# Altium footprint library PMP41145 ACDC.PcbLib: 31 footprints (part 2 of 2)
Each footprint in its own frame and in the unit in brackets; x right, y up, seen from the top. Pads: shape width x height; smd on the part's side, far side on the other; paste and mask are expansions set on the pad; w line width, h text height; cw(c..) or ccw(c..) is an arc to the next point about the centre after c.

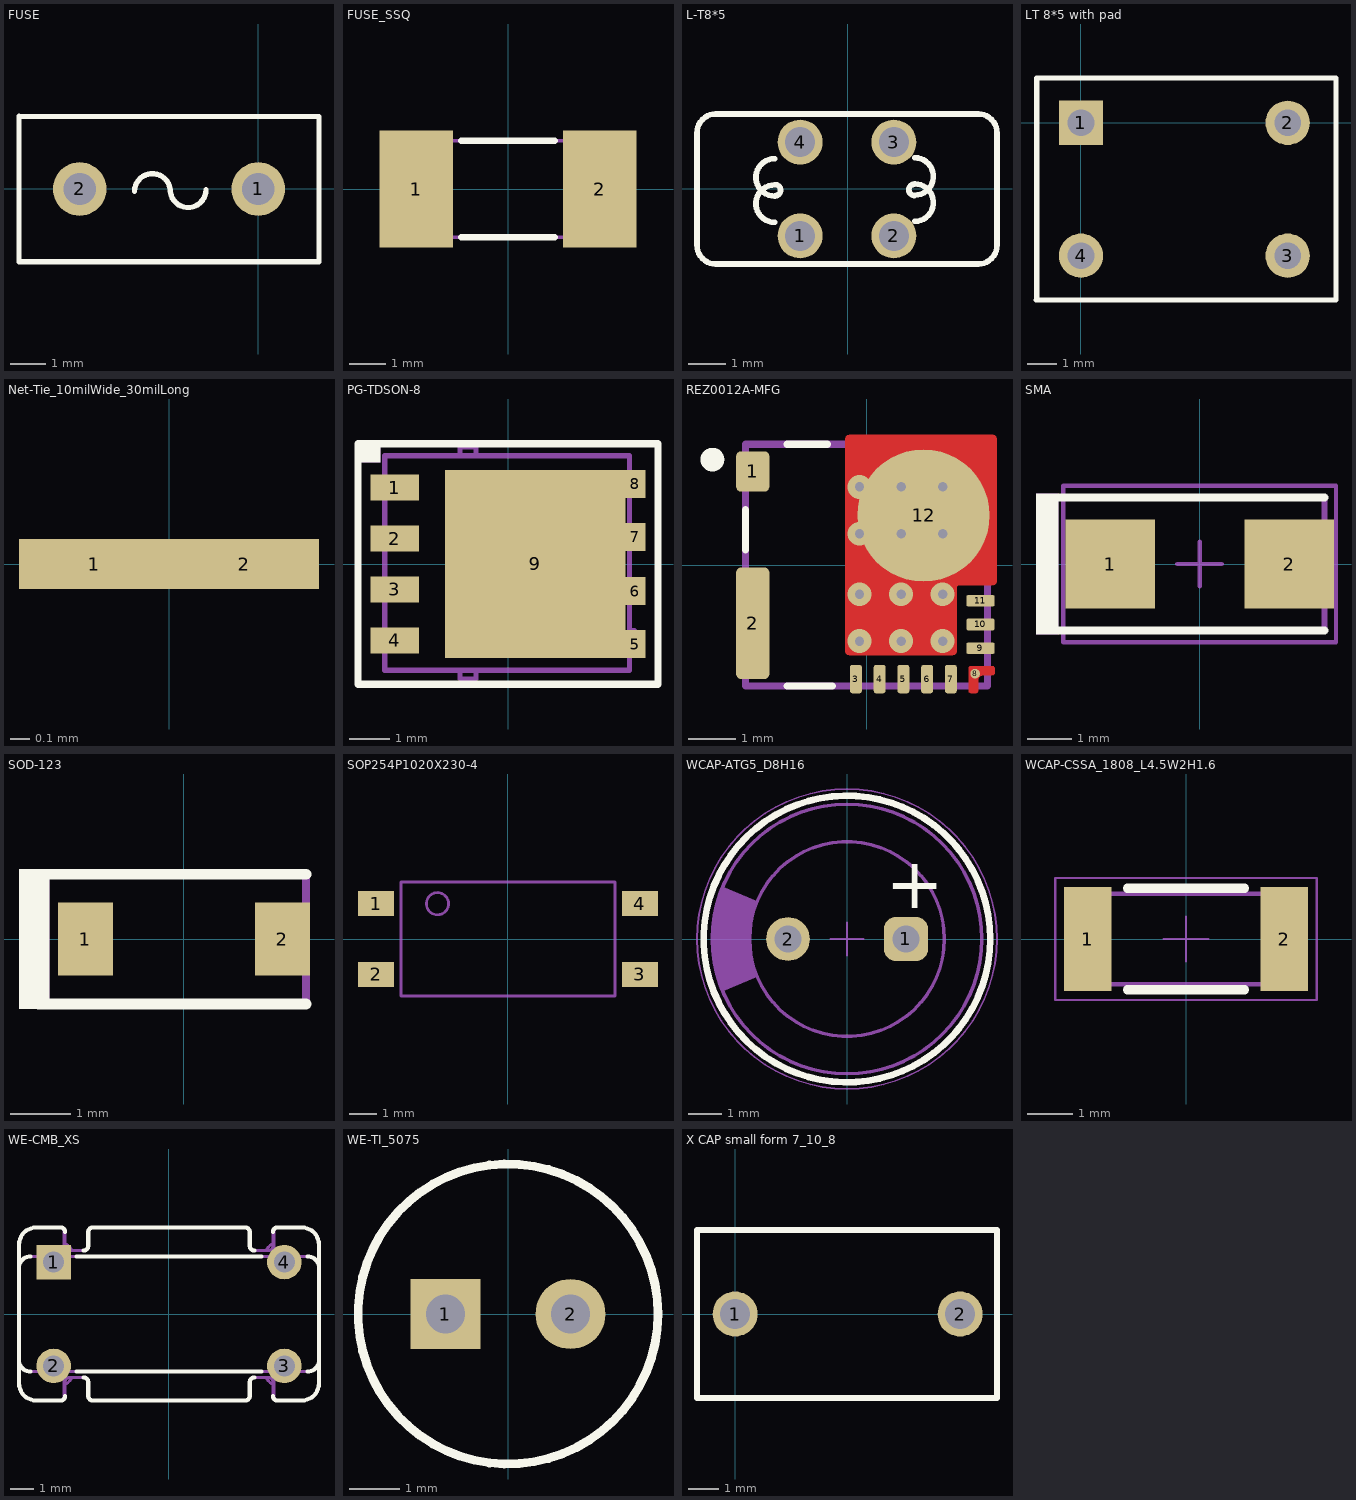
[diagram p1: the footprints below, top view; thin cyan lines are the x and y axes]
## FUSE [mm]
height 0.9
pads (2):
  round 1.5 hole 0.9: 1(0,0) 2(-5,0)
Top Overlay:
  lines w0.15: -3.465,-0.068 cw(c-2.965,-0.068) -2.465,-0.068 ; -2.465,-0.018 ccw(c-1.965,-0.018) -1.465,-0.018 ; -6.7,-2.032 -6.7,2.032 1.7,2.032 1.7,-2.032 -6.7,-2.032
3D body: height 5, standoff 0, extent -6.7,-2.032 1.7,2.032

## FUSE_SSQ [mm] "Bel Fuse"
height 2.64
pads (2):
  rect 2x3.18 smd: 1(-2.5,0) 2(2.5,0)
Top Overlay:
  lines w0.178: -1.27,-1.32 1.27,-1.32 ; -1.27,1.32 1.27,1.32
Mechanical 5:
  lines w0.1: -3.175,-1.32 3.175,-1.32 3.175,1.32 -3.175,1.32 -3.175,-1.32
  text ".Designator" at -2.032,-0.508 h1.02
3D body: height 2.64, standoff 0, extent -3.175,-1.32 3.17,1.32

## L-T8*5 [mm]
height 1
pads (4):
  round 1.2 hole 0.8: 1(-1.272,-1.253) 2(1.228,-1.253) 3(1.228,1.247) 4(-1.272,1.247)
Top Overlay:
  lines w0.15: -1.951,-0.892 cw(c-1.951,-0.392) -1.951,0.108 ; -1.951,-0.193 cw(c-1.951,0.307) -1.951,0.807 ; -1.943,-0.185 ccw(c-1.943,-0.035) -1.943,0.115 ; 1.776,-0.175 cw(c1.776,-0.025) 1.776,0.125 ; 1.784,-0.867 ccw(c1.784,-0.367) 1.784,0.133 ; 1.784,-0.168 ccw(c1.784,0.332) 1.784,0.832 ; -4.022,-1.503 ccw(c-3.522,-1.503) -3.522,-2.003 3.478,-2.003 ccw(c3.478,-1.503) 3.978,-1.503 3.978,1.497 ccw(c3.478,1.497) 3.478,1.997 -3.522,1.997 ccw(c-3.522,1.497) -4.022,1.497 -4.022,-1.503
3D body "lf2.stp": height 10, standoff 0, extent -4.9,-2.9 5.1,3.1

## LT 8*5 with pad [mm] "WE-CMB Series Size XS"
height 18
pads (4):
  rect 1.5x1.5 hole 0.9: 1(0,0)
  round 1.5 hole 0.9: 2(7,0) 3(7,-4.5) 4(0,-4.5)
Top Overlay:
  lines w0.178: -1.524,-6 8.636,-6 8.636,1.517 -1.5,1.517 -1.5,-4.25 -1.5,-6

## Net-Tie_10milWide_30milLong [mil] "10mil net tie, no solder mask opening, no solder paste"
pads (2):
  rect 30x10 smd paste-5 mask-5: 1(-15,0) 2(15,0)

## PG-TDSON-8 [mm] "Infineon recommended land pattern"
height 1.1
pads (9):
  rect 1.2x0.65 smd: 1(-2.825,1.905) 2(-2.825,0.635) 3(-2.825,-0.635) 4(-2.825,-1.905)
  rect 0.5x0.7 smd: 5(3.175,-2) 6(3.175,-0.675) 7(3.175,0.675) 8(3.175,2)
  rect 4.5x4.7 smd paste-2.25: 9(0.675,0)
Top Overlay:
  rectangle: -3.742,2.528 -3.177,2.975
  lines w0.178: -3.74,-3 -0.105,-3 3.74,-3 3.74,0 3.74,3 0.105,3 -3.74,3 -3.74,0 -3.74,-3
Top Paste:
  rectangle: -1.475,-2.25 -0.242,-0.95
  rectangle: -1.475,-0.65 -0.242,0.65
  rectangle: 1.591,-2.25 2.824,-0.95
  rectangle: 0.058,-0.65 1.291,0.65
  rectangle: 0.058,-2.25 1.291,-0.95
  rectangle: -1.475,0.95 -0.242,2.25
  rectangle: 1.591,-0.65 2.824,0.65
  rectangle: 0.058,0.95 1.291,2.25
  rectangle: 1.591,0.95 2.824,2.25
Mechanical 5:
  rectangle: -3.742,2.528 -3.177,2.975
  lines w0.127: -3.075,-2.1 -3.2,-2.1 -3.2,-1.66 -3.075,-1.66 ; -3.075,-0.83 -3.2,-0.83 -3.2,-0.39 -3.075,-0.39 ; -3.075,0.44 -3.2,0.44 -3.2,0.88 -3.075,0.88 ; -3.075,1.71 -3.2,1.71 -3.2,2.15 -3.075,2.15 ; -1.2,-2.65 -1.2,-2.87 -0.8,-2.87 -0.8,-2.65 ; -1.2,2.7 -1.2,2.92 -0.8,2.92 -0.8,2.7 ; 3.025,-2.1 3.15,-2.1 3.15,-1.66 3.025,-1.66 ; 3.025,-0.83 3.15,-0.83 3.15,-0.39 3.025,-0.39 ; 3.025,0.44 3.15,0.44 3.15,0.88 3.025,0.88 ; 3.025,1.71 3.15,1.71 3.15,2.15 3.025,2.15 ; -3.075,-2.65 3.025,-2.65 3.025,2.7 -3.075,2.7 -3.075,-2.65
  text ".Designator" at -1.925,-0.5 h1.02
3D body "PG-TDSON-8.stp": height 1.1, standoff 0, extent -3.175,-2.895 3.175,2.895

## REZ0012A-MFG [mm]
pads (12):
  rrect29% 0.7x0.85 smd paste-1000 mask-1000: 1(-2.4,1.975)
  rrect29% 0.7x2.35 smd paste-1000 mask-1000: 2(-2.4,-1.225)
  rrect40% 0.25x0.6 smd paste+0 mask+0: 3(-0.225,-2.4) 4(0.275,-2.4) 5(0.775,-2.4) 6(1.275,-2.4) 7(1.775,-2.4)
  round 0.203 smd paste+0 mask+0: 8(2.288,-2.288)
  rrect40% 0.6x0.25 smd paste+0 mask+0: 9(2.4,-1.75) 10(2.4,-1.25) 11(2.4,-0.75)
  round 2.788 smd paste-1000 mask-1000: 12(1.199,1.048)
via -0.15,-1.6 diameter 0.5 hole 0.2
via 0.725,-1.6 diameter 0.5 hole 0.2
via 1.6,-1.6 diameter 0.5 hole 0.2
via -0.15,-0.61 diameter 0.5 hole 0.2
via 0.725,-0.61 diameter 0.5 hole 0.2
via 1.6,-0.61 diameter 0.5 hole 0.2
via -0.15,0.66 diameter 0.5 hole 0.2
via 0.725,0.66 diameter 0.5 hole 0.2
via 1.6,0.66 diameter 0.5 hole 0.2
via 1.6,1.65 diameter 0.5 hole 0.2
via 0.725,1.65 diameter 0.5 hole 0.2
via -0.15,1.65 diameter 0.5 hole 0.2
Top Layer:
  region: -0.45,2.65 -0.45,2.67 -0.435,2.707 -0.407,2.735 -0.37,2.75 -0.35,2.75 2.648,2.75 2.668,2.75 2.705,2.735 2.733,2.707 2.748,2.67 2.748,2.65 2.748,-0.325 2.748,-0.345 2.733,-0.382 2.705,-0.41 2.668,-0.425 2.648,-0.425 1.95,-0.425 1.94,-0.426 1.922,-0.433 1.908,-0.447 1.901,-0.465 1.9,-0.475 1.9,-1.8 1.9,-1.82 1.885,-1.857 1.857,-1.885 1.82,-1.9 1.8,-1.9 -0.35,-1.9 -0.37,-1.9 -0.407,-1.885 -0.435,-1.857 -0.45,-1.82 -0.45,-1.8
  region: 2.2,-2.7 2.19,-2.7 2.172,-2.692 2.158,-2.678 2.15,-2.66 2.15,-2.65 2.15,-2.175 2.15,-2.165 2.158,-2.147 2.172,-2.133 2.19,-2.125 2.2,-2.125 2.65,-2.125 2.66,-2.125 2.678,-2.133 2.692,-2.147 2.7,-2.165 2.7,-2.175 2.7,-2.275 2.7,-2.285 2.692,-2.303 2.678,-2.317 2.66,-2.325 2.65,-2.325 2.45,-2.325 2.43,-2.327 2.394,-2.342 2.367,-2.369 2.352,-2.405 2.35,-2.425 2.35,-2.65 2.35,-2.66 2.342,-2.678 2.328,-2.692 2.31,-2.7 2.3,-2.7
Top Overlay:
  circle w0.25: c-3.25,2.225 r0.125
  lines w0.15: -2.55,0.325 -2.55,1.175 ; -1.675,-2.55 -0.725,-2.55 ; -1.675,2.55 -0.825,2.55
Top Paste:
  drawing of 20 lines, arcs and shapes, not listed
Top Solder:
  drawing of 4 lines, arcs and shapes, not listed
Mechanical 5:
  lines w0.15: -2.55,-2.55 -2.55,2.55 2.55,2.55 2.55,-2.55 -2.55,-2.55
  text ".Designator" at 0.049,0.242 h0.5
3D body "IC_UCG28682_VQFN12.STEP": height 1, standoff 0, extent -2.5,-2.5 2.5,2.5

## SMA [mm] "Molded Diode, 2-Leads, Body 4.3x2.6mm, IPC Medium Density, based on OnSemi component dimensions and land pattern"
height 2.27
pads (2):
  rect 2x2 smd: 1(-2,0) 2(2,0)
Top Overlay:
  rectangle: -3.657,-1.576 -3.149,1.574
  lines w0.178: -3.327,-1.486 2.794,-1.486 ; -3.327,1.486 2.794,1.486
Mechanical 5:
  rectangle: -3.657,-1.576 -3.149,1.574
  lines w0.127: -3.327,-1.486 2.794,-1.486 2.794,1.486 -3.327,1.486
  text ".Designator" at -2.769,-0.33 h1.02
Mechanical 15:
  lines w0.1: -0.5,0 0.5,0 ; 0,-0.5 0,0.5 ; -3.05,-1.75 -3.05,1.75 3.05,1.75 3.05,-1.75 -3.05,-1.75
3D body "SMA_nominal.stp": height 2.42, standoff 0.02, extent -2.6,-1.3 2.6,1.3

## SOD-123 [mm] "On Semi recommended land pattern"
height 1.35
pads (2):
  rect 0.915x1.22 smd: 1(-1.637,0) 2(1.637,0)
Top Overlay:
  rectangle: -2.743,-1.168 -2.235,1.169
  lines w0.178: -2.413,-1.079 2.032,-1.079 ; -2.413,1.079 2.032,1.079
Mechanical 5:
  rectangle: -2.743,-1.168 -2.235,1.169
  lines w0.127: -2.413,-1.079 2.032,-1.079 2.032,1.079 -2.413,1.079
  text ".Designator" at -1.956,-0.33 h0.76
3D body "SOD-123.stp": height 1.35, standoff 0, extent -1.932,-0.9 1.932,0.9

## SOP254P1020X230-4 [mm] "VISHAY"
height 2
pads (4):
  rect 1.3x0.9 smd: 1(-4.75,1.27) 2(-4.75,-1.27) 3(4.75,-1.27) 4(4.75,1.27)
Mechanical 5:
  circle w0.1: c-2.54,1.27 r0.4
  lines w0.1: -3.85,-2.05 3.85,-2.05 3.85,2.05 -3.85,2.05 -3.85,-2.05
  text ".Designator" at -1.6,-0.3 h0.8
3D body: height 2.02, standoff 0, extent -2.939,0.871 -2.141,1.669
3D body: height 2, standoff 0, extent -3.849,-2.049 3.849,2.049

## WCAP-ATG5_D8H16 [mm] "Aluminum Electrolytic Capacitors, 8x16mm"
height 16
pads (2):
  rrect50% 1.3x1.3 hole 0.8: 1(1.75,0)
  round 1.3 hole 0.8: 2(-1.75,0)
Top Overlay:
  circle w0.2: c0,0 r4.25
  text "+" at 1.153,0.913 h1.5
Mechanical 3:
  text ".Designator" at -5.998,-0.4 h1.2
Mechanical 11:
  circle w0.1: c0,0 r2.89
  circle w0.1: c0,0 r4
  region: -3.685,-1.557 -3.762,-1.372 -3.881,-0.99 -3.96,-0.598 -4,-0.2 -4,0.2 -3.96,0.598 -3.881,0.99 -3.762,1.372 -3.685,1.557 -2.662,1.125 -2.662,1.124 -2.715,0.99 -2.8,0.714 -2.858,0.431 -2.886,0.144 -2.886,-0.144 -2.858,-0.431 -2.8,-0.714 -2.715,-0.99 -2.662,-1.124 -2.662,-1.125
Mechanical 15:
  circle w0.05: c0,0 r4.45
  lines w0.05: -0.5,0 0.5,0 ; 0,-0.5 0,0.5
3D body "8x16x3.5x0.5.stp": height 16.31, standoff -19.91, extent -3.99,-4 4,3.999

## WCAP-CSSA_1808_L4.5W2H1.6 [mm] "Ceramic Capacitors, body 4.50x2.00mm"
height 1.6
pads (2):
  rect 1.05x2.3 smd: 1(-2.175,0) 2(2.175,0)
Top Overlay:
  lines w0.2: -1.3,-1.125 1.3,-1.125 ; -1.3,1.125 1.3,1.125
Top Component Outline:
  lines w0.1: -2.25,-1 -2.25,1 2.25,1 2.25,-1 -2.25,-1
Top 3D Body:
  lines w0.1: -2.25,-1 -2.25,1 2.25,1 2.25,-1 -2.25,-1
Top Courtyard:
  lines w0.05: -2.9,-1.35 -2.9,1.35 2.9,1.35 2.9,-1.35 -2.9,-1.35
Top Component Center:
  lines w0.05: -0.5,0 0.5,0 ; 0,-0.5 0,0.5
Top Designator:
  text ".Designator" at -4.998,-0.333 h1
3D body "1808.step": height 1.6, standoff 0, extent -2.25,-1 2.25,1

## WE-CMB_XS [mm] "WE-CMB Series Size XS"
height 18
pads (4):
  rect 1.5x1.5 hole 0.9: 1(-5,2.25)
  round 1.5 hole 0.9: 2(-5,-2.25) 3(5,-2.25) 4(5,2.25)
Top Overlay:
  lines w0.178: -6,-2.5 cw(c-6,-2) -6.5,-2 ; -6,2.5 ccw(c-6,2) -6.5,2 ; -4.5,-3.55 cw(c-4.7,-3.55) -4.543,-3.674 cw(c-4.7,-3.55) -4.7,-3.75 -5.75,-3.75 cw(c-5.75,-3) -6.5,-3 -6.5,-2 ; -4.5,3.55 ccw(c-4.7,3.55) -4.543,3.674 ccw(c-4.7,3.55) -4.7,3.75 -5.75,3.75 ccw(c-5.75,3) -6.5,3 -6.5,2 ; -4,-2.5 0,-2.5 4,-2.5 ; -4,2.5 0,2.5 4,2.5 ; -3.7,-2.75 cw(c-3.7,-2.95) -3.5,-2.95 -3.5,-3.55 ccw(c-3.3,-3.55) -3.3,-3.75 3.3,-3.75 ccw(c3.3,-3.55) 3.5,-3.55 3.5,-2.95 cw(c3.7,-2.95) 3.7,-2.75 ; -3.7,2.75 ccw(c-3.7,2.95) -3.5,2.95 -3.5,3.55 cw(c-3.3,3.55) -3.3,3.75 3.3,3.75 cw(c3.3,3.55) 3.5,3.55 3.5,2.95 ccw(c3.7,2.95) 3.7,2.75 ; 4.5,-3.55 ccw(c4.7,-3.55) 4.543,-3.674 ccw(c4.7,-3.55) 4.7,-3.75 5.75,-3.75 ccw(c5.75,-3) 6.5,-3 6.5,-2 ; 4.5,3.55 cw(c4.7,3.55) 4.543,3.674 cw(c4.7,3.55) 4.7,3.75 5.75,3.75 cw(c5.75,3) 6.5,3 6.5,2 ; 6,-2.5 ccw(c6,-2) 6.5,-2 ; 6,2.5 cw(c6,2) 6.5,2 ; -6.5,-2 -6.5,2 ; 6.5,-2 6.5,2
Mechanical 5:
  lines w0.127: -4.543,-2.5 -4.543,-3.674 ; -4.543,2.5 -4.543,3.674 ; -4.5,-3.058 ccw(c-5,-2.25) -4.192,-2.75 ; -4.5,3.058 cw(c-5,2.25) -4.192,2.75 ; 4.192,-2.75 ccw(c5,-2.25) 4.5,-3.058 ; 4.192,2.75 cw(c5,2.25) 4.5,3.058 ; 4.543,-2.5 4.543,-3.674 ; 4.543,2.5 4.543,3.674 ; -6.5,-2 ccw(c-6,-2) -6,-2.5 0,-2.5 6,-2.5 ccw(c6,-2) 6.5,-2 ; -6.5,-2 -6.5,2 ; -6.5,-2 -6.5,-3 ccw(c-5.75,-3) -5.75,-3.75 -4.7,-3.75 ccw(c-4.7,-3.55) -4.543,-3.674 ; -6.5,2 cw(c-6,2) -6,2.5 0,2.5 6,2.5 cw(c6,2) 6.5,2 ; -6.5,2 -6.5,3 cw(c-5.75,3) -5.75,3.75 -4.7,3.75 cw(c-4.7,3.55) -4.543,3.674 ; -4.543,-3.674 ccw(c-4.7,-3.55) -4.5,-3.55 -4.5,-2.95 cw(c-4.3,-2.95) -4.3,-2.75 -3.7,-2.75 cw(c-3.7,-2.95) -3.5,-2.95 -3.5,-3.55 ccw(c-3.3,-3.55) -3.3,-3.75 3.3,-3.75 ccw(c3.3,-3.55) 3.5,-3.55 3.5,-2.95 cw(c3.7,-2.95) 3.7,-2.75 4.3,-2.75 cw(c4.3,-2.95) 4.5,-2.95 4.5,-3.55 ccw(c4.7,-3.55) 4.543,-3.674 ; -4.543,3.674 cw(c-4.7,3.55) -4.5,3.55 -4.5,2.95 ccw(c-4.3,2.95) -4.3,2.75 -3.7,2.75 ccw(c-3.7,2.95) -3.5,2.95 -3.5,3.55 cw(c-3.3,3.55) -3.3,3.75 3.3,3.75 cw(c3.3,3.55) 3.5,3.55 3.5,2.95 ccw(c3.7,2.95) 3.7,2.75 4.3,2.75 ccw(c4.3,2.95) 4.5,2.95 4.5,3.55 cw(c4.7,3.55) 4.543,3.674 ; 4.543,-3.674 ccw(c4.7,-3.55) 4.7,-3.75 5.75,-3.75 ccw(c5.75,-3) 6.5,-3 6.5,-2 ; 4.543,3.674 cw(c4.7,3.55) 4.7,3.75 5.75,3.75 cw(c5.75,3) 6.5,3 6.5,2 ; 6.5,-2 6.5,2
  text ".Designator" at -2.65,-0.375 h0.61
3D body "WE-CMB_XS.stp": height 16.24, standoff -3.58, extent -6.5,-3.75 6.5,3.75

## WE-TI_5075 [mm] "Wurth WE-TI 5075"
height 8.5
pads (2):
  rect 1.4x1.4 hole 0.787: 1(-1.25,0)
  round 1.4 hole 0.787: 2(1.25,0)
Top Overlay:
  circle w0.177: c0,0 r3
Mechanical 5:
  circle w0.1: c0,0 r3
  text ".Designator" at -1.992,-0.508 h1.02
3D body: height 8.5, standoff 0, extent -2.999,-2.999 2.999,2.999

## X CAP small form 7_10_8 [mm]
height 15
pads (2):
  round 1.5 hole 1: 1(0,0) 2(7.5,0)
Top Overlay:
  lines w0.2: -1.27,-2.794 -1.27,2.794 8.73,2.794 8.73,-2.794 -1.27,-2.794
